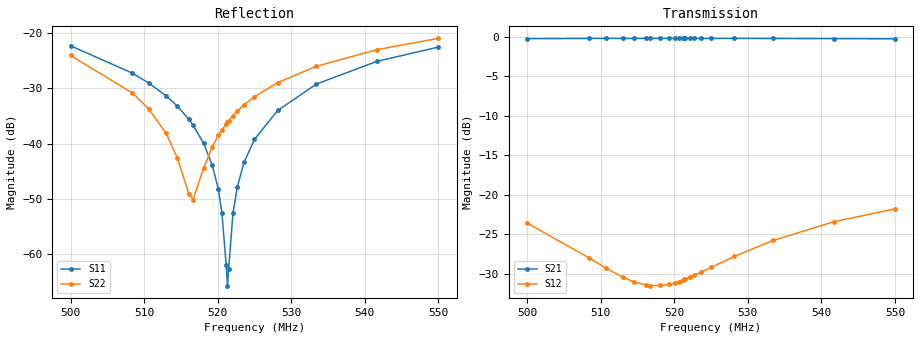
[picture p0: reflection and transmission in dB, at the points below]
! MS46524B
! 12345/M1: Not Set/M2: Not Set
! 4/27/2021 9:14:43 PM
! C:\USERS\KOBYRNE\DESKTOP\0.5 - 0.55 GHZ (D4I0555).S2P
! CHANNEL.1
! TR.MEASUREMENT
! RAW.DATA
# GHZ S RI R 50.0
! FREQ.GHZ  S11RE  S11IM  S21RE  S21IM  S12RE  S12IM  S22RE  S22IM
!; PortSelection: Port_12
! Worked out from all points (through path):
!   601 points, 500 MHz to 550 MHz, reference 50 ohm
!   highest |S21| = -0.17 dB at 520.6 MHz (marker M1); lowest = -0.2 dB at 550 MHz (marker M2)
!   lowest |S11| = -65.7 dB at 521.3 MHz (marker M3), VSWR 1.00, Z = 50 + j0.0447 ohm
!   |S11| at or under -10 dB: start of sweep to end of sweep
!   |S22| runs from -50.1 to -21.0 dB; largest |S21 - S12| = 1
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0.5  0.0591 0.0481  -0.7379 0.64  0.0547 0.0373  0.0532 0.0326
0.5084167  0.0341 0.0264  -0.6579 0.726  0.0396 0.00398  0.0256 0.0126
0.5106667  0.0277 0.0214  -0.6349 0.7469  0.0342 -0.00337  0.0188 0.00796
0.513  0.0213 0.0164  -0.6101 0.7676  0.0282 -0.0103  0.0118 0.00352
0.5145  0.0173 0.0133  -0.5938 0.7803  0.0241 -0.0144  0.00741 0.00084
0.5160833  0.0131 0.0101  -0.5766 0.7934  0.0197 -0.0183  0.00291 -0.00196
0.5166667  0.0115 0.00899  -0.5702 0.7979  0.0179 -0.0196  0.00132 -0.00283
0.5180833  0.00788 0.00623  -0.5543 0.8091  0.0138 -0.0228  -0.00277 -0.00529
0.51925  0.00492 0.00416  -0.5411 0.818  0.0103 -0.025  -0.00594 -0.0071
0.5200833  0.00286 0.00265  -0.5317 0.8241  0.00773 -0.0266  -0.00832 -0.00844
0.5205833  0.00159 0.00172  -0.5263 0.8278  0.00617 -0.0274  -0.00962 -0.00918
0.5211667  0.00013 0.000788  -0.5195 0.832  0.00433 -0.0285  -0.0112 -0.0101
0.5213333  -0.000267 0.000447  -0.5175 0.8333  0.00378 -0.0289  -0.0116 -0.0103
0.5215  -0.000711 0.00021  -0.5155 0.8343  0.00335 -0.0291  -0.0121 -0.0106
0.5220833  -0.0022 -0.00081  -0.509 0.8385  0.00156 -0.03  -0.0136 -0.0115
0.5226667  -0.00359 -0.00185  -0.5021 0.8424  -0.000215 -0.0309  -0.0152 -0.0124
0.5235833  -0.00581 -0.00345  -0.4915 0.8486  -0.00314 -0.0321  -0.0177 -0.0136
0.525  -0.00924 -0.00575  -0.4749 0.858  -0.00767 -0.0338  -0.0213 -0.0156
0.5281667  -0.0168 -0.0106  -0.4373 0.8772  -0.0178 -0.0366  -0.0295 -0.0197
0.5334167  -0.0291 -0.0183  -0.3735 0.9052  -0.0342 -0.0383  -0.0425 -0.0259
0.5416667  -0.0473 -0.0284  -0.2712 0.9388  -0.0582 -0.0341  -0.0616 -0.0339
0.55  -0.0647 -0.0363  -0.1662 0.9603  -0.0783 -0.0224  -0.0797 -0.0395
